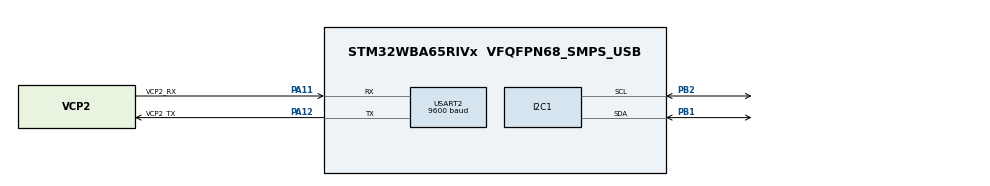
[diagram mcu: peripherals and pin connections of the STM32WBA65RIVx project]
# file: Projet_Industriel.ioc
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CORTEX_M33_NS.userName=CORTEX_M33
I2C1.Timing=0xA0101722
Mcu.Family=STM32WBA
Mcu.Name=STM32WBA65RIVx
Mcu.Package=VFQFPN68_SMPS_USB
NUCLEO-WBA65RI.BUTTON=1
NUCLEO-WBA65RI.BUTTON2=1
NUCLEO-WBA65RI.BUTTON3=1
NUCLEO-WBA65RI.LD1=true
NUCLEO-WBA65RI.LD2=true
NUCLEO-WBA65RI.LD3=true
NUCLEO-WBA65RI.VCP=true
NVIC.EXTI13_IRQn=true\:0\:0\:false\:false\:true\:false\:true\:true
NVIC.EXTI4_IRQn=true\:0\:0\:false\:false\:true\:false\:true\:true
NVIC.EXTI5_IRQn=true\:0\:0\:false\:false\:true\:false\:true\:true
NVIC.PriorityGroup=NVIC_PRIORITYGROUP_4
OSC_IN.GPIO_Label=OSC_IN
OSC_IN.Signal=RCC_OSC_IN
OSC_OUT.GPIO_Label=OSC_OUT
OSC_OUT.Signal=RCC_OSC_OUT
PA11.GPIO_Label=VCP2_RX
PA11.GPIO_PuPd=GPIO_PULLUP
PA11.GPIO_Speed=GPIO_SPEED_FREQ_HIGH
PA11.Mode=Asynchronous
PA11.Signal=USART2_RX
PA12.GPIO_Label=VCP2_TX
PA12.GPIO_PuPd=GPIO_PULLUP
PA12.GPIO_Speed=GPIO_SPEED_FREQ_HIGH
PA12.Mode=Asynchronous
PA12.Signal=USART2_TX
PA13(JTMS/SWDIO).GPIO_Label=JTMS/SWDIO
PA13(JTMS/SWDIO).Signal=DEBUG_JTMS-SWDIO
PA14(JTCK/SWCLK).GPIO_Label=JTCLK/SWCLK
PA14(JTCK/SWCLK).Signal=DEBUG_JTCK-SWCLK
PA15(JTDI).GPIO_Label=VCP2_RTS
PA15(JTDI).GPIO_PuPd=GPIO_PULLUP
PA15(JTDI).GPIO_Speed=GPIO_SPEED_FREQ_HIGH
PA15(JTDI).Signal=USART2_RTS
PA8.Signal=USART1_RX
PB1.Mode=I2C
PB1.Signal=I2C1_SDA
PB12.Signal=USART1_TX
PB15.GPIO_Label=VCP2_CTS
PB15.GPIO_PuPd=GPIO_PULLUP
PB15.GPIO_Speed=GPIO_SPEED_FREQ_HIGH
PB15.Signal=USART2_CTS
PB2.Mode=I2C
PB2.Signal=I2C1_SCL
PB3(JTDO/TRACESWO).GPIO_Label=JTDO/SWO
PB3(JTDO/TRACESWO).Signal=DEBUG_JTDO-SWO
PC14-OSC32_IN.GPIO_Label=OSC32_IN
PC14-OSC32_IN.Signal=RCC_OSC32_IN
PC15-OSC32_OUT.GPIO_Label=OSC32_OUT
PC15-OSC32_OUT.Signal=RCC_OSC32_OUT
PD6.GPIO_Label=USB_FS_P
PD6.Signal=USB_OTG_HS_DP
PD7.GPIO_Label=USB_FS_N
PD7.Signal=USB_OTG_HS_DM
ProjectManager.HeapSize=0x200
ProjectManager.StackSize=0x400
ProjectManager.TargetToolchain=STM32CubeIDE
RCC.ADCFreq_Value=66000000
RCC.AHB5CLKDivider=DIV4
RCC.AHBFreq_Value=66000000
RCC.APB1Freq_Value=66000000
RCC.APB1TimFreq_Value=66000000
RCC.APB2Freq_Value=66000000
RCC.APB2TimFreq_Value=66000000
RCC.CortexFreq_Value=8250000
RCC.HCLKFreq_Value=66000000
RCC.HSE_VALUE=32000000
RCC.HSI_VALUE=16000000
RCC.LSE_VALUE=32768
RCC.LSI1_VALUE=32000
RCC.LSI2_VALUE=32000
RCC.PLLFRACN=4096
RCC.PLLM=2
RCC.PLLN=16
RCC.SYSCLKFreq_VALUE=66000000
RCC.SYSCLKSourceVirtual=RCC_SYSCLKSOURCE_PLLCLK
RCC.VCOOutputFreq_Value=132000000
USART2.BaudRate=9600
USART2.VirtualMode-Asynchronous=VM_ASYNC
VP_CORTEX_M33_NS_VS_Hclk.Mode=Hclk_Mode
VP_MEMORYMAP_VS_MEMORYMAP.Mode=CurAppReg
VP_NUCLEO-WBA65RI_VS_BSP_COMMON.Mode=COMMON
VP_PWR_VS_SECSignals.Mode=Security/Privilege
board=NUCLEO-WBA65RI

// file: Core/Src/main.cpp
/* USER CODE BEGIN Header */
/**
  ******************************************************************************
  * @file           : main.c
  * @brief          : Main program body
  ******************************************************************************
  * @attention
  *
  * Copyright (c) 2026 STMicroelectronics.
  * All rights reserved.
  *
  * This software is licensed under terms that can be found in the LICENSE file
  * in the root directory of this software component.
  * If no LICENSE file comes with this software, it is provided AS-IS.
  *
  ******************************************************************************
  */
/* USER CODE END Header */
#include "main.h"
#include <stdio.h>
#include <string.h>

/* USER CODE BEGIN Includes */
#include "DFRobot_HX711_I2C.h"

/* USER CODE END Includes */

/* USER CODE BEGIN PD */

// Définition de l'adresse I2C du HX711 (0x64 par défaut)
#define POIDS_ETALONNAGE 200
#define SEUIL_DETECTION_CALIBRATION 20

#define CALIBRATION_VALUE  1987.430054f

#define POIDS_SEUIL 100

/* USER CODE END PD */

COM_InitTypeDef BspCOMInit;

I2C_HandleTypeDef hi2c1;

UART_HandleTypeDef huart2;

/* USER CODE BEGIN PV */
DFRobot_HX711_I2C MyScale(&hi2c1, HX711_I2C_ADDR);
/* USER CODE END PV */

void SystemClock_Config(void);
static void MX_GPIO_Init(void);
static void MX_I2C1_Init(void);
static void MX_USART2_UART_Init(void);

/* USER CODE BEGIN 0 */

// Lignes pour la lecture dans le terminal
extern "C" int _write(int fd, char *ptr, int len)
{
    (void)fd;
    HAL_UART_Transmit(&huart2, (uint8_t *)ptr, len, HAL_MAX_DELAY);
    return len;
}
/* USER CODE END 0 */

int main(void)
{

  /* MCU Configuration--------------------------------------------------------*/

  /* Reset of all peripherals, Initializes the Flash interface and the Systick. */
  HAL_Init();

  /* Configure the system clock */
  SystemClock_Config();

  /* Initialize all configured peripherals */
  MX_GPIO_Init();
  MX_I2C1_Init();
  MX_USART2_UART_Init();
  /* USER CODE BEGIN 2 */

  // Initialisation du capteur
    if (!MyScale.begin()){
  	  printf("Erreur : Capteur HX711 non detecte\r\n");
  	  while (1) {HAL_Delay(1000);}
    }
    printf("HX711 initialise avec succes !\r\n");

    // Calibration effectuée donc plus besoin de ces lignes
    /*
    // Configuration de la calibration du capteur
    MyScale.setCalWeight(POIDS_ETALONNAGE); // poids de référence
    MyScale.setThreshold(SEUIL_DETECTION_CALIBRATION); // Seuil de detection

    // Tare
    MyScale.peel();
    HAL_Delay(500); // Petite attente pour laisser du temps au capteur

    // Calibration
    printf("Placez un objet de %d\r\n", POIDS_ETALONNAGE);
    MyScale.enableCal();

    uint32_t startTime = HAL_GetTick();
    while (!MyScale.getCalFlag()) {
  	  HAL_Delay(1000);
  	  if ((HAL_GetTick() - startTime) > 7000) {
  		  printf("Echec de la calibration !\r\n");
  		  break;
  	  }
    }

    // Sauvegarde de la valeur de calibration
    float calibrationValue = MyScale.getCalibration();
    if (calibrationValue > 100) {	// 100 valeur arbitraire à verifier
    	MyScale.setCalibration(calibrationValue);
  	  	printf("Calibration terminee. Valeur de calibration : %f\r\n", calibrationValue);
    } else {
    	printf("Erreur : Aucune calibration. \r\n");
    }*/

    // Calibration fixe
    MyScale.setCalibration(CALIBRATION_VALUE);

    // Tare
    printf("La balance doit etre vide \r\n");
    HAL_Delay(1000);
    MyScale.peel();
    HAL_Delay(500);
    printf("Tare effectuee \r\n");

  /* USER CODE END 2 */

  /* Initialize leds */
  BSP_LED_Init(LED_BLUE);
  BSP_LED_Init(LED_GREEN);
  BSP_LED_Init(LED_RED);

  /* Initialize USER push-button, will be used to trigger an interrupt each time it's pressed.*/
  BSP_PB_Init(B1, BUTTON_MODE_EXTI);
  BSP_PB_Init(B2, BUTTON_MODE_EXTI);
  BSP_PB_Init(B3, BUTTON_MODE_EXTI);

  /* Initialize COM1 port (115200, 8 bits (7-bit data + 1 stop bit), no parity */
  BspCOMInit.BaudRate   = 115200;
  BspCOMInit.WordLength = COM_WORDLENGTH_8B;
  BspCOMInit.StopBits   = COM_STOPBITS_1;
  BspCOMInit.Parity     = COM_PARITY_NONE;
  BspCOMInit.HwFlowCtl  = COM_HWCONTROL_NONE;
  if (BSP_COM_Init(COM1, &BspCOMInit) != BSP_ERROR_NONE)
  {
    Error_Handler();
  }

  /* Infinite loop */
  /* USER CODE BEGIN WHILE */
  while (1)
  {
	  // Test de la balance
	  float weight = MyScale.readWeight(20); // moyenne sur 20 valeurs
	  printf("Poids : %f\r\n", weight);

	  // Le delai sera a modifier pour correspondre a l'usage
	  HAL_Delay(1000);

	  if(weight < POIDS_SEUIL){
		  // Partie a modifier pour envoyer une alerte
		  printf(" --- Alert plus de cafe --- \r\n");
	  }

    /* USER CODE END WHILE */

  }
}

void SystemClock_Config(void)
{
  RCC_OscInitTypeDef RCC_OscInitStruct = {0};
  RCC_ClkInitTypeDef RCC_ClkInitStruct = {0};

  /** Supply configuration update enable
  */
  HAL_PWREx_ConfigSupply(PWR_LDO_SUPPLY);

  /** Configure the main internal regulator output voltage
  */
  if (HAL_PWREx_ControlVoltageScaling(PWR_REGULATOR_VOLTAGE_SCALE1) != HAL_OK)
  {
    Error_Handler();
  }

  /** Initializes the CPU, AHB and APB busses clocks
  */
  RCC_OscInitStruct.OscillatorType = RCC_OSCILLATORTYPE_HSI;
  RCC_OscInitStruct.HSIState = RCC_HSI_ON;
  RCC_OscInitStruct.HSICalibrationValue = RCC_HSICALIBRATION_DEFAULT;
  RCC_OscInitStruct.PLL1.PLLState = RCC_PLL_ON;
  RCC_OscInitStruct.PLL1.PLLSource = RCC_PLLSOURCE_HSI;
  RCC_OscInitStruct.PLL1.PLLM = 2;
  RCC_OscInitStruct.PLL1.PLLN = 16;
  RCC_OscInitStruct.PLL1.PLLP = 2;
  RCC_OscInitStruct.PLL1.PLLQ = 2;
  RCC_OscInitStruct.PLL1.PLLR = 2;
  RCC_OscInitStruct.PLL1.PLLFractional = 4096;
  if (HAL_RCC_OscConfig(&RCC_OscInitStruct) != HAL_OK)
  {
    Error_Handler();
  }

  /** Initializes the CPU, AHB and APB busses clocks
  */
  RCC_ClkInitStruct.ClockType = RCC_CLOCKTYPE_HCLK|RCC_CLOCKTYPE_SYSCLK
                              |RCC_CLOCKTYPE_PCLK1|RCC_CLOCKTYPE_PCLK2
                              |RCC_CLOCKTYPE_PCLK7|RCC_CLOCKTYPE_HCLK5;
  RCC_ClkInitStruct.SYSCLKSource = RCC_SYSCLKSOURCE_PLLCLK;
  RCC_ClkInitStruct.AHBCLKDivider = RCC_SYSCLK_DIV1;
  RCC_ClkInitStruct.APB1CLKDivider = RCC_HCLK_DIV1;
  RCC_ClkInitStruct.APB2CLKDivider = RCC_HCLK_DIV1;
  RCC_ClkInitStruct.APB7CLKDivider = RCC_HCLK_DIV1;
  RCC_ClkInitStruct.AHB5_PLL1_CLKDivider = RCC_SYSCLK_PLL1_DIV4;
  RCC_ClkInitStruct.AHB5_HSEHSI_CLKDivider = RCC_SYSCLK_HSEHSI_DIV1;

  if (HAL_RCC_ClockConfig(&RCC_ClkInitStruct, FLASH_LATENCY_2) != HAL_OK)
  {
    Error_Handler();
  }
}

static void MX_I2C1_Init(void)
{

  hi2c1.Instance = I2C1;
  hi2c1.Init.Timing = 0xA0101722;
  hi2c1.Init.OwnAddress1 = 0;
  hi2c1.Init.AddressingMode = I2C_ADDRESSINGMODE_7BIT;
  hi2c1.Init.DualAddressMode = I2C_DUALADDRESS_DISABLE;
  hi2c1.Init.OwnAddress2 = 0;
  hi2c1.Init.OwnAddress2Masks = I2C_OA2_NOMASK;
  hi2c1.Init.GeneralCallMode = I2C_GENERALCALL_DISABLE;
  hi2c1.Init.NoStretchMode = I2C_NOSTRETCH_DISABLE;
  if (HAL_I2C_Init(&hi2c1) != HAL_OK)
  {
    Error_Handler();
  }

  /** Configure Analogue filter
  */
  if (HAL_I2CEx_ConfigAnalogFilter(&hi2c1, I2C_ANALOGFILTER_ENABLE) != HAL_OK)
  {
    Error_Handler();
  }

  /** Configure Digital filter
  */
  if (HAL_I2CEx_ConfigDigitalFilter(&hi2c1, 0) != HAL_OK)
  {
    Error_Handler();
  }

}

static void MX_USART2_UART_Init(void)
{

  huart2.Instance = USART2;
  huart2.Init.BaudRate = 9600;
  huart2.Init.WordLength = UART_WORDLENGTH_8B;
  huart2.Init.StopBits = UART_STOPBITS_1;
  huart2.Init.Parity = UART_PARITY_NONE;
  huart2.Init.Mode = UART_MODE_TX_RX;
  huart2.Init.HwFlowCtl = UART_HWCONTROL_NONE;
  huart2.Init.OverSampling = UART_OVERSAMPLING_16;
  huart2.Init.OneBitSampling = UART_ONE_BIT_SAMPLE_DISABLE;
  huart2.Init.ClockPrescaler = UART_PRESCALER_DIV1;
  huart2.AdvancedInit.AdvFeatureInit = UART_ADVFEATURE_NO_INIT;
  if (HAL_UART_Init(&huart2) != HAL_OK)
  {
    Error_Handler();
  }
  if (HAL_UARTEx_SetTxFifoThreshold(&huart2, UART_TXFIFO_THRESHOLD_1_8) != HAL_OK)
  {
    Error_Handler();
  }
  if (HAL_UARTEx_SetRxFifoThreshold(&huart2, UART_RXFIFO_THRESHOLD_1_8) != HAL_OK)
  {
    Error_Handler();
  }
  if (HAL_UARTEx_DisableFifoMode(&huart2) != HAL_OK)
  {
    Error_Handler();
  }

}

static void MX_GPIO_Init(void)
{
  GPIO_InitTypeDef GPIO_InitStruct = {0};

  /* GPIO Ports Clock Enable */
  __HAL_RCC_GPIOD_CLK_ENABLE();
  __HAL_RCC_GPIOC_CLK_ENABLE();
  __HAL_RCC_GPIOB_CLK_ENABLE();
  __HAL_RCC_GPIOA_CLK_ENABLE();

  /*Configure GPIO pins : USB_FS_N_Pin USB_FS_P_Pin */
  GPIO_InitStruct.Pin = USB_FS_N_Pin|USB_FS_P_Pin;
  GPIO_InitStruct.Mode = GPIO_MODE_AF_PP;
  GPIO_InitStruct.Pull = GPIO_NOPULL;
  GPIO_InitStruct.Speed = GPIO_SPEED_FREQ_LOW;
  HAL_GPIO_Init(GPIOD, &GPIO_InitStruct);

}

void Error_Handler(void)
{
  __disable_irq();
  while (1)
  {
  }
}
